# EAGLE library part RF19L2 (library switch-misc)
RAFI SWITCH

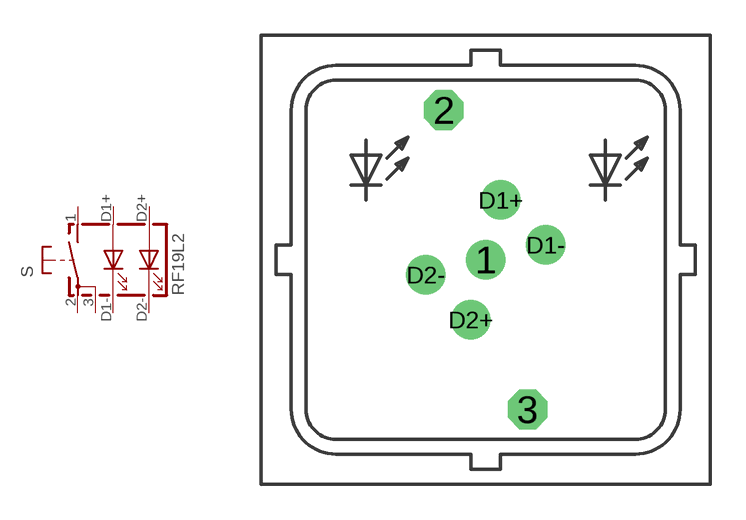
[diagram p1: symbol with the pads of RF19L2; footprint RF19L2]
Designator prefix S

## RF19L2  [RF19L2]
1  S  pas
2  P  pas
3  P  pas
D1+  A1  pas
D1-  C1  pas
D2+  A2  pas
D2-  C2  pas

## Footprint RF19L2 (pad centres in mm)
RAFI SWITCH
drill 1.118 round: 1 0,0; D1+ 0.635,2.54; D1- 2.54,0.635; D2+ -0.635,-2.54; D2- -2.54,-0.635
drill 1.118 octagon: 2 -1.778,6.35; 3 1.778,-6.35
